# Generated by innovus_enablement/scripts/gen_fakeram.py: abstract 32x32 SRAM.
# Geometry is an assumption (see script header), not PDK data.
VERSION 5.8 ;
BUSBITCHARS "[]" ;
DIVIDERCHAR "/" ;

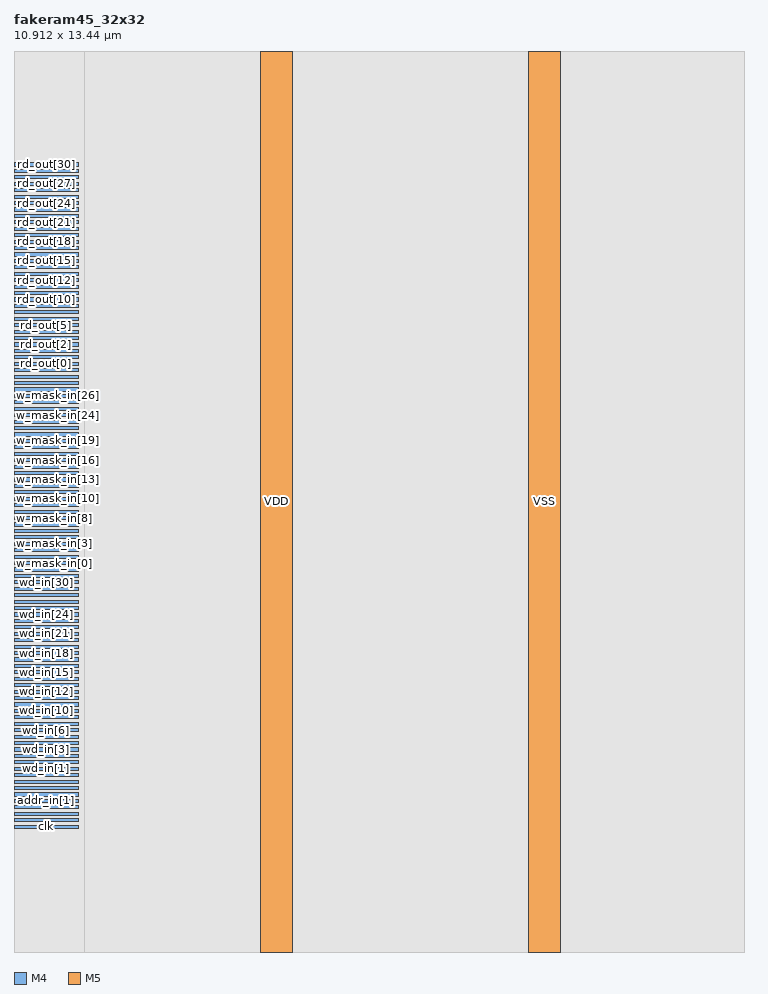
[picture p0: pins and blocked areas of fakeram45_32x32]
MACRO fakeram45_32x32
  CLASS BLOCK ;
  FOREIGN fakeram45_32x32 0 0 ;
  ORIGIN 0 0 ;
  SIZE 10.9120 BY 13.4400 ;
  SYMMETRY X Y R90 ;
  PIN clk
    DIRECTION INPUT ;
    USE CLOCK ;
    PORT
      LAYER M4 ;
        RECT 0 1.8480 0.9600 1.8960 ;
    END
  END clk
  PIN ce_in
    DIRECTION INPUT ;
    USE SIGNAL ;
    PORT
      LAYER M4 ;
        RECT 0 1.9440 0.9600 1.9920 ;
    END
  END ce_in
  PIN we_in
    DIRECTION INPUT ;
    USE SIGNAL ;
    PORT
      LAYER M4 ;
        RECT 0 2.0400 0.9600 2.0880 ;
    END
  END we_in
  PIN addr_in[0]
    DIRECTION INPUT ;
    USE SIGNAL ;
    PORT
      LAYER M4 ;
        RECT 0 2.1360 0.9600 2.1840 ;
    END
  END addr_in[0]
  PIN addr_in[1]
    DIRECTION INPUT ;
    USE SIGNAL ;
    PORT
      LAYER M4 ;
        RECT 0 2.2320 0.9600 2.2800 ;
    END
  END addr_in[1]
  PIN addr_in[2]
    DIRECTION INPUT ;
    USE SIGNAL ;
    PORT
      LAYER M4 ;
        RECT 0 2.3280 0.9600 2.3760 ;
    END
  END addr_in[2]
  PIN addr_in[3]
    DIRECTION INPUT ;
    USE SIGNAL ;
    PORT
      LAYER M4 ;
        RECT 0 2.4240 0.9600 2.4720 ;
    END
  END addr_in[3]
  PIN addr_in[4]
    DIRECTION INPUT ;
    USE SIGNAL ;
    PORT
      LAYER M4 ;
        RECT 0 2.5200 0.9600 2.5680 ;
    END
  END addr_in[4]
  PIN wd_in[0]
    DIRECTION INPUT ;
    USE SIGNAL ;
    PORT
      LAYER M4 ;
        RECT 0 2.6160 0.9600 2.6640 ;
    END
  END wd_in[0]
  PIN wd_in[1]
    DIRECTION INPUT ;
    USE SIGNAL ;
    PORT
      LAYER M4 ;
        RECT 0 2.7120 0.9600 2.7600 ;
    END
  END wd_in[1]
  PIN wd_in[2]
    DIRECTION INPUT ;
    USE SIGNAL ;
    PORT
      LAYER M4 ;
        RECT 0 2.8080 0.9600 2.8560 ;
    END
  END wd_in[2]
  PIN wd_in[3]
    DIRECTION INPUT ;
    USE SIGNAL ;
    PORT
      LAYER M4 ;
        RECT 0 2.9040 0.9600 2.9520 ;
    END
  END wd_in[3]
  PIN wd_in[4]
    DIRECTION INPUT ;
    USE SIGNAL ;
    PORT
      LAYER M4 ;
        RECT 0 3.0000 0.9600 3.0480 ;
    END
  END wd_in[4]
  PIN wd_in[5]
    DIRECTION INPUT ;
    USE SIGNAL ;
    PORT
      LAYER M4 ;
        RECT 0 3.0960 0.9600 3.1440 ;
    END
  END wd_in[5]
  PIN wd_in[6]
    DIRECTION INPUT ;
    USE SIGNAL ;
    PORT
      LAYER M4 ;
        RECT 0 3.1920 0.9600 3.2400 ;
    END
  END wd_in[6]
  PIN wd_in[7]
    DIRECTION INPUT ;
    USE SIGNAL ;
    PORT
      LAYER M4 ;
        RECT 0 3.2880 0.9600 3.3360 ;
    END
  END wd_in[7]
  PIN wd_in[8]
    DIRECTION INPUT ;
    USE SIGNAL ;
    PORT
      LAYER M4 ;
        RECT 0 3.3840 0.9600 3.4320 ;
    END
  END wd_in[8]
  PIN wd_in[9]
    DIRECTION INPUT ;
    USE SIGNAL ;
    PORT
      LAYER M4 ;
        RECT 0 3.4800 0.9600 3.5280 ;
    END
  END wd_in[9]
  PIN wd_in[10]
    DIRECTION INPUT ;
    USE SIGNAL ;
    PORT
      LAYER M4 ;
        RECT 0 3.5760 0.9600 3.6240 ;
    END
  END wd_in[10]
  PIN wd_in[11]
    DIRECTION INPUT ;
    USE SIGNAL ;
    PORT
      LAYER M4 ;
        RECT 0 3.6720 0.9600 3.7200 ;
    END
  END wd_in[11]
  PIN wd_in[12]
    DIRECTION INPUT ;
    USE SIGNAL ;
    PORT
      LAYER M4 ;
        RECT 0 3.7680 0.9600 3.8160 ;
    END
  END wd_in[12]
  PIN wd_in[13]
    DIRECTION INPUT ;
    USE SIGNAL ;
    PORT
      LAYER M4 ;
        RECT 0 3.8640 0.9600 3.9120 ;
    END
  END wd_in[13]
  PIN wd_in[14]
    DIRECTION INPUT ;
    USE SIGNAL ;
    PORT
      LAYER M4 ;
        RECT 0 3.9600 0.9600 4.0080 ;
    END
  END wd_in[14]
  PIN wd_in[15]
    DIRECTION INPUT ;
    USE SIGNAL ;
    PORT
      LAYER M4 ;
        RECT 0 4.0560 0.9600 4.1040 ;
    END
  END wd_in[15]
  PIN wd_in[16]
    DIRECTION INPUT ;
    USE SIGNAL ;
    PORT
      LAYER M4 ;
        RECT 0 4.1520 0.9600 4.2000 ;
    END
  END wd_in[16]
  PIN wd_in[17]
    DIRECTION INPUT ;
    USE SIGNAL ;
    PORT
      LAYER M4 ;
        RECT 0 4.2480 0.9600 4.2960 ;
    END
  END wd_in[17]
  PIN wd_in[18]
    DIRECTION INPUT ;
    USE SIGNAL ;
    PORT
      LAYER M4 ;
        RECT 0 4.3440 0.9600 4.3920 ;
    END
  END wd_in[18]
  PIN wd_in[19]
    DIRECTION INPUT ;
    USE SIGNAL ;
    PORT
      LAYER M4 ;
        RECT 0 4.4400 0.9600 4.4880 ;
    END
  END wd_in[19]
  PIN wd_in[20]
    DIRECTION INPUT ;
    USE SIGNAL ;
    PORT
      LAYER M4 ;
        RECT 0 4.5360 0.9600 4.5840 ;
    END
  END wd_in[20]
  PIN wd_in[21]
    DIRECTION INPUT ;
    USE SIGNAL ;
    PORT
      LAYER M4 ;
        RECT 0 4.6320 0.9600 4.6800 ;
    END
  END wd_in[21]
  PIN wd_in[22]
    DIRECTION INPUT ;
    USE SIGNAL ;
    PORT
      LAYER M4 ;
        RECT 0 4.7280 0.9600 4.7760 ;
    END
  END wd_in[22]
  PIN wd_in[23]
    DIRECTION INPUT ;
    USE SIGNAL ;
    PORT
      LAYER M4 ;
        RECT 0 4.8240 0.9600 4.8720 ;
    END
  END wd_in[23]
  PIN wd_in[24]
    DIRECTION INPUT ;
    USE SIGNAL ;
    PORT
      LAYER M4 ;
        RECT 0 4.9200 0.9600 4.9680 ;
    END
  END wd_in[24]
  PIN wd_in[25]
    DIRECTION INPUT ;
    USE SIGNAL ;
    PORT
      LAYER M4 ;
        RECT 0 5.0160 0.9600 5.0640 ;
    END
  END wd_in[25]
  PIN wd_in[26]
    DIRECTION INPUT ;
    USE SIGNAL ;
    PORT
      LAYER M4 ;
        RECT 0 5.1120 0.9600 5.1600 ;
    END
  END wd_in[26]
  PIN wd_in[27]
    DIRECTION INPUT ;
    USE SIGNAL ;
    PORT
      LAYER M4 ;
        RECT 0 5.2080 0.9600 5.2560 ;
    END
  END wd_in[27]
  PIN wd_in[28]
    DIRECTION INPUT ;
    USE SIGNAL ;
    PORT
      LAYER M4 ;
        RECT 0 5.3040 0.9600 5.3520 ;
    END
  END wd_in[28]
  PIN wd_in[29]
    DIRECTION INPUT ;
    USE SIGNAL ;
    PORT
      LAYER M4 ;
        RECT 0 5.4000 0.9600 5.4480 ;
    END
  END wd_in[29]
  PIN wd_in[30]
    DIRECTION INPUT ;
    USE SIGNAL ;
    PORT
      LAYER M4 ;
        RECT 0 5.4960 0.9600 5.5440 ;
    END
  END wd_in[30]
  PIN wd_in[31]
    DIRECTION INPUT ;
    USE SIGNAL ;
    PORT
      LAYER M4 ;
        RECT 0 5.5920 0.9600 5.6400 ;
    END
  END wd_in[31]
  PIN w_mask_in[0]
    DIRECTION INPUT ;
    USE SIGNAL ;
    PORT
      LAYER M4 ;
        RECT 0 5.6880 0.9600 5.7360 ;
    END
  END w_mask_in[0]
  PIN w_mask_in[1]
    DIRECTION INPUT ;
    USE SIGNAL ;
    PORT
      LAYER M4 ;
        RECT 0 5.7840 0.9600 5.8320 ;
    END
  END w_mask_in[1]
  PIN w_mask_in[2]
    DIRECTION INPUT ;
    USE SIGNAL ;
    PORT
      LAYER M4 ;
        RECT 0 5.8800 0.9600 5.9280 ;
    END
  END w_mask_in[2]
  PIN w_mask_in[3]
    DIRECTION INPUT ;
    USE SIGNAL ;
    PORT
      LAYER M4 ;
        RECT 0 5.9760 0.9600 6.0240 ;
    END
  END w_mask_in[3]
  PIN w_mask_in[4]
    DIRECTION INPUT ;
    USE SIGNAL ;
    PORT
      LAYER M4 ;
        RECT 0 6.0720 0.9600 6.1200 ;
    END
  END w_mask_in[4]
  PIN w_mask_in[5]
    DIRECTION INPUT ;
    USE SIGNAL ;
    PORT
      LAYER M4 ;
        RECT 0 6.1680 0.9600 6.2160 ;
    END
  END w_mask_in[5]
  PIN w_mask_in[6]
    DIRECTION INPUT ;
    USE SIGNAL ;
    PORT
      LAYER M4 ;
        RECT 0 6.2640 0.9600 6.3120 ;
    END
  END w_mask_in[6]
  PIN w_mask_in[7]
    DIRECTION INPUT ;
    USE SIGNAL ;
    PORT
      LAYER M4 ;
        RECT 0 6.3600 0.9600 6.4080 ;
    END
  END w_mask_in[7]
  PIN w_mask_in[8]
    DIRECTION INPUT ;
    USE SIGNAL ;
    PORT
      LAYER M4 ;
        RECT 0 6.4560 0.9600 6.5040 ;
    END
  END w_mask_in[8]
  PIN w_mask_in[9]
    DIRECTION INPUT ;
    USE SIGNAL ;
    PORT
      LAYER M4 ;
        RECT 0 6.5520 0.9600 6.6000 ;
    END
  END w_mask_in[9]
  PIN w_mask_in[10]
    DIRECTION INPUT ;
    USE SIGNAL ;
    PORT
      LAYER M4 ;
        RECT 0 6.6480 0.9600 6.6960 ;
    END
  END w_mask_in[10]
  PIN w_mask_in[11]
    DIRECTION INPUT ;
    USE SIGNAL ;
    PORT
      LAYER M4 ;
        RECT 0 6.7440 0.9600 6.7920 ;
    END
  END w_mask_in[11]
  PIN w_mask_in[12]
    DIRECTION INPUT ;
    USE SIGNAL ;
    PORT
      LAYER M4 ;
        RECT 0 6.8400 0.9600 6.8880 ;
    END
  END w_mask_in[12]
  PIN w_mask_in[13]
    DIRECTION INPUT ;
    USE SIGNAL ;
    PORT
      LAYER M4 ;
        RECT 0 6.9360 0.9600 6.9840 ;
    END
  END w_mask_in[13]
  PIN w_mask_in[14]
    DIRECTION INPUT ;
    USE SIGNAL ;
    PORT
      LAYER M4 ;
        RECT 0 7.0320 0.9600 7.0800 ;
    END
  END w_mask_in[14]
  PIN w_mask_in[15]
    DIRECTION INPUT ;
    USE SIGNAL ;
    PORT
      LAYER M4 ;
        RECT 0 7.1280 0.9600 7.1760 ;
    END
  END w_mask_in[15]
  PIN w_mask_in[16]
    DIRECTION INPUT ;
    USE SIGNAL ;
    PORT
      LAYER M4 ;
        RECT 0 7.2240 0.9600 7.2720 ;
    END
  END w_mask_in[16]
  PIN w_mask_in[17]
    DIRECTION INPUT ;
    USE SIGNAL ;
    PORT
      LAYER M4 ;
        RECT 0 7.3200 0.9600 7.3680 ;
    END
  END w_mask_in[17]
  PIN w_mask_in[18]
    DIRECTION INPUT ;
    USE SIGNAL ;
    PORT
      LAYER M4 ;
        RECT 0 7.4160 0.9600 7.4640 ;
    END
  END w_mask_in[18]
  PIN w_mask_in[19]
    DIRECTION INPUT ;
    USE SIGNAL ;
    PORT
      LAYER M4 ;
        RECT 0 7.5120 0.9600 7.5600 ;
    END
  END w_mask_in[19]
  PIN w_mask_in[20]
    DIRECTION INPUT ;
    USE SIGNAL ;
    PORT
      LAYER M4 ;
        RECT 0 7.6080 0.9600 7.6560 ;
    END
  END w_mask_in[20]
  PIN w_mask_in[21]
    DIRECTION INPUT ;
    USE SIGNAL ;
    PORT
      LAYER M4 ;
        RECT 0 7.7040 0.9600 7.7520 ;
    END
  END w_mask_in[21]
  PIN w_mask_in[22]
    DIRECTION INPUT ;
    USE SIGNAL ;
    PORT
      LAYER M4 ;
        RECT 0 7.8000 0.9600 7.8480 ;
    END
  END w_mask_in[22]
  PIN w_mask_in[23]
    DIRECTION INPUT ;
    USE SIGNAL ;
    PORT
      LAYER M4 ;
        RECT 0 7.8960 0.9600 7.9440 ;
    END
  END w_mask_in[23]
  PIN w_mask_in[24]
    DIRECTION INPUT ;
    USE SIGNAL ;
    PORT
      LAYER M4 ;
        RECT 0 7.9920 0.9600 8.0400 ;
    END
  END w_mask_in[24]
  PIN w_mask_in[25]
    DIRECTION INPUT ;
    USE SIGNAL ;
    PORT
      LAYER M4 ;
        RECT 0 8.0880 0.9600 8.1360 ;
    END
  END w_mask_in[25]
  PIN w_mask_in[26]
    DIRECTION INPUT ;
    USE SIGNAL ;
    PORT
      LAYER M4 ;
        RECT 0 8.1840 0.9600 8.2320 ;
    END
  END w_mask_in[26]
  PIN w_mask_in[27]
    DIRECTION INPUT ;
    USE SIGNAL ;
    PORT
      LAYER M4 ;
        RECT 0 8.2800 0.9600 8.3280 ;
    END
  END w_mask_in[27]
  PIN w_mask_in[28]
    DIRECTION INPUT ;
    USE SIGNAL ;
    PORT
      LAYER M4 ;
        RECT 0 8.3760 0.9600 8.4240 ;
    END
  END w_mask_in[28]
  PIN w_mask_in[29]
    DIRECTION INPUT ;
    USE SIGNAL ;
    PORT
      LAYER M4 ;
        RECT 0 8.4720 0.9600 8.5200 ;
    END
  END w_mask_in[29]
  PIN w_mask_in[30]
    DIRECTION INPUT ;
    USE SIGNAL ;
    PORT
      LAYER M4 ;
        RECT 0 8.5680 0.9600 8.6160 ;
    END
  END w_mask_in[30]
  PIN w_mask_in[31]
    DIRECTION INPUT ;
    USE SIGNAL ;
    PORT
      LAYER M4 ;
        RECT 0 8.6640 0.9600 8.7120 ;
    END
  END w_mask_in[31]
  PIN rd_out[0]
    DIRECTION OUTPUT ;
    USE SIGNAL ;
    PORT
      LAYER M4 ;
        RECT 0 8.7600 0.9600 8.8080 ;
    END
  END rd_out[0]
  PIN rd_out[1]
    DIRECTION OUTPUT ;
    USE SIGNAL ;
    PORT
      LAYER M4 ;
        RECT 0 8.8560 0.9600 8.9040 ;
    END
  END rd_out[1]
  PIN rd_out[2]
    DIRECTION OUTPUT ;
    USE SIGNAL ;
    PORT
      LAYER M4 ;
        RECT 0 8.9520 0.9600 9.0000 ;
    END
  END rd_out[2]
  PIN rd_out[3]
    DIRECTION OUTPUT ;
    USE SIGNAL ;
    PORT
      LAYER M4 ;
        RECT 0 9.0480 0.9600 9.0960 ;
    END
  END rd_out[3]
  PIN rd_out[4]
    DIRECTION OUTPUT ;
    USE SIGNAL ;
    PORT
      LAYER M4 ;
        RECT 0 9.1440 0.9600 9.1920 ;
    END
  END rd_out[4]
  PIN rd_out[5]
    DIRECTION OUTPUT ;
    USE SIGNAL ;
    PORT
      LAYER M4 ;
        RECT 0 9.2400 0.9600 9.2880 ;
    END
  END rd_out[5]
  PIN rd_out[6]
    DIRECTION OUTPUT ;
    USE SIGNAL ;
    PORT
      LAYER M4 ;
        RECT 0 9.3360 0.9600 9.3840 ;
    END
  END rd_out[6]
  PIN rd_out[7]
    DIRECTION OUTPUT ;
    USE SIGNAL ;
    PORT
      LAYER M4 ;
        RECT 0 9.4320 0.9600 9.4800 ;
    END
  END rd_out[7]
  PIN rd_out[8]
    DIRECTION OUTPUT ;
    USE SIGNAL ;
    PORT
      LAYER M4 ;
        RECT 0 9.5280 0.9600 9.5760 ;
    END
  END rd_out[8]
  PIN rd_out[9]
    DIRECTION OUTPUT ;
    USE SIGNAL ;
    PORT
      LAYER M4 ;
        RECT 0 9.6240 0.9600 9.6720 ;
    END
  END rd_out[9]
  PIN rd_out[10]
    DIRECTION OUTPUT ;
    USE SIGNAL ;
    PORT
      LAYER M4 ;
        RECT 0 9.7200 0.9600 9.7680 ;
    END
  END rd_out[10]
  PIN rd_out[11]
    DIRECTION OUTPUT ;
    USE SIGNAL ;
    PORT
      LAYER M4 ;
        RECT 0 9.8160 0.9600 9.8640 ;
    END
  END rd_out[11]
  PIN rd_out[12]
    DIRECTION OUTPUT ;
    USE SIGNAL ;
    PORT
      LAYER M4 ;
        RECT 0 9.9120 0.9600 9.9600 ;
    END
  END rd_out[12]
  PIN rd_out[13]
    DIRECTION OUTPUT ;
    USE SIGNAL ;
    PORT
      LAYER M4 ;
        RECT 0 10.0080 0.9600 10.0560 ;
    END
  END rd_out[13]
  PIN rd_out[14]
    DIRECTION OUTPUT ;
    USE SIGNAL ;
    PORT
      LAYER M4 ;
        RECT 0 10.1040 0.9600 10.1520 ;
    END
  END rd_out[14]
  PIN rd_out[15]
    DIRECTION OUTPUT ;
    USE SIGNAL ;
    PORT
      LAYER M4 ;
        RECT 0 10.2000 0.9600 10.2480 ;
    END
  END rd_out[15]
  PIN rd_out[16]
    DIRECTION OUTPUT ;
    USE SIGNAL ;
    PORT
      LAYER M4 ;
        RECT 0 10.2960 0.9600 10.3440 ;
    END
  END rd_out[16]
  PIN rd_out[17]
    DIRECTION OUTPUT ;
    USE SIGNAL ;
    PORT
      LAYER M4 ;
        RECT 0 10.3920 0.9600 10.4400 ;
    END
  END rd_out[17]
  PIN rd_out[18]
    DIRECTION OUTPUT ;
    USE SIGNAL ;
    PORT
      LAYER M4 ;
        RECT 0 10.4880 0.9600 10.5360 ;
    END
  END rd_out[18]
  PIN rd_out[19]
    DIRECTION OUTPUT ;
    USE SIGNAL ;
    PORT
      LAYER M4 ;
        RECT 0 10.5840 0.9600 10.6320 ;
    END
  END rd_out[19]
  PIN rd_out[20]
    DIRECTION OUTPUT ;
    USE SIGNAL ;
    PORT
      LAYER M4 ;
        RECT 0 10.6800 0.9600 10.7280 ;
    END
  END rd_out[20]
  PIN rd_out[21]
    DIRECTION OUTPUT ;
    USE SIGNAL ;
    PORT
      LAYER M4 ;
        RECT 0 10.7760 0.9600 10.8240 ;
    END
  END rd_out[21]
  PIN rd_out[22]
    DIRECTION OUTPUT ;
    USE SIGNAL ;
    PORT
      LAYER M4 ;
        RECT 0 10.8720 0.9600 10.9200 ;
    END
  END rd_out[22]
  PIN rd_out[23]
    DIRECTION OUTPUT ;
    USE SIGNAL ;
    PORT
      LAYER M4 ;
        RECT 0 10.9680 0.9600 11.0160 ;
    END
  END rd_out[23]
  PIN rd_out[24]
    DIRECTION OUTPUT ;
    USE SIGNAL ;
    PORT
      LAYER M4 ;
        RECT 0 11.0640 0.9600 11.1120 ;
    END
  END rd_out[24]
  PIN rd_out[25]
    DIRECTION OUTPUT ;
    USE SIGNAL ;
    PORT
      LAYER M4 ;
        RECT 0 11.1600 0.9600 11.2080 ;
    END
  END rd_out[25]
  PIN rd_out[26]
    DIRECTION OUTPUT ;
    USE SIGNAL ;
    PORT
      LAYER M4 ;
        RECT 0 11.2560 0.9600 11.3040 ;
    END
  END rd_out[26]
  PIN rd_out[27]
    DIRECTION OUTPUT ;
    USE SIGNAL ;
    PORT
      LAYER M4 ;
        RECT 0 11.3520 0.9600 11.4000 ;
    END
  END rd_out[27]
  PIN rd_out[28]
    DIRECTION OUTPUT ;
    USE SIGNAL ;
    PORT
      LAYER M4 ;
        RECT 0 11.4480 0.9600 11.4960 ;
    END
  END rd_out[28]
  PIN rd_out[29]
    DIRECTION OUTPUT ;
    USE SIGNAL ;
    PORT
      LAYER M4 ;
        RECT 0 11.5440 0.9600 11.5920 ;
    END
  END rd_out[29]
  PIN rd_out[30]
    DIRECTION OUTPUT ;
    USE SIGNAL ;
    PORT
      LAYER M4 ;
        RECT 0 11.6400 0.9600 11.6880 ;
    END
  END rd_out[30]
  PIN rd_out[31]
    DIRECTION OUTPUT ;
    USE SIGNAL ;
    PORT
      LAYER M4 ;
        RECT 0 11.7360 0.9600 11.7840 ;
    END
  END rd_out[31]
  PIN VDD
    DIRECTION INOUT ;
    USE POWER ;
    PORT
      LAYER M5 ;
        RECT 3.6800 0 4.1600 13.4400 ;
    END
  END VDD
  PIN VSS
    DIRECTION INOUT ;
    USE GROUND ;
    PORT
      LAYER M5 ;
        RECT 7.6800 0 8.1600 13.4400 ;
    END
  END VSS
  OBS
    LAYER M0 ;
      RECT 0 0 10.9120 13.4400 ;
    LAYER M1 ;
      RECT 0 0 10.9120 13.4400 ;
    LAYER M2 ;
      RECT 0 0 10.9120 13.4400 ;
    LAYER M3 ;
      RECT 0 0 10.9120 13.4400 ;
    LAYER VIA0 ;
      RECT 0 0 10.9120 13.4400 ;
    LAYER VIA1 ;
      RECT 0 0 10.9120 13.4400 ;
    LAYER VIA2 ;
      RECT 0 0 10.9120 13.4400 ;
    LAYER VIA3 ;
      RECT 0 0 10.9120 13.4400 ;
    LAYER M4 ;
      RECT 1.0560 0 10.9120 13.4400 ;
  END
END fakeram45_32x32

END LIBRARY
